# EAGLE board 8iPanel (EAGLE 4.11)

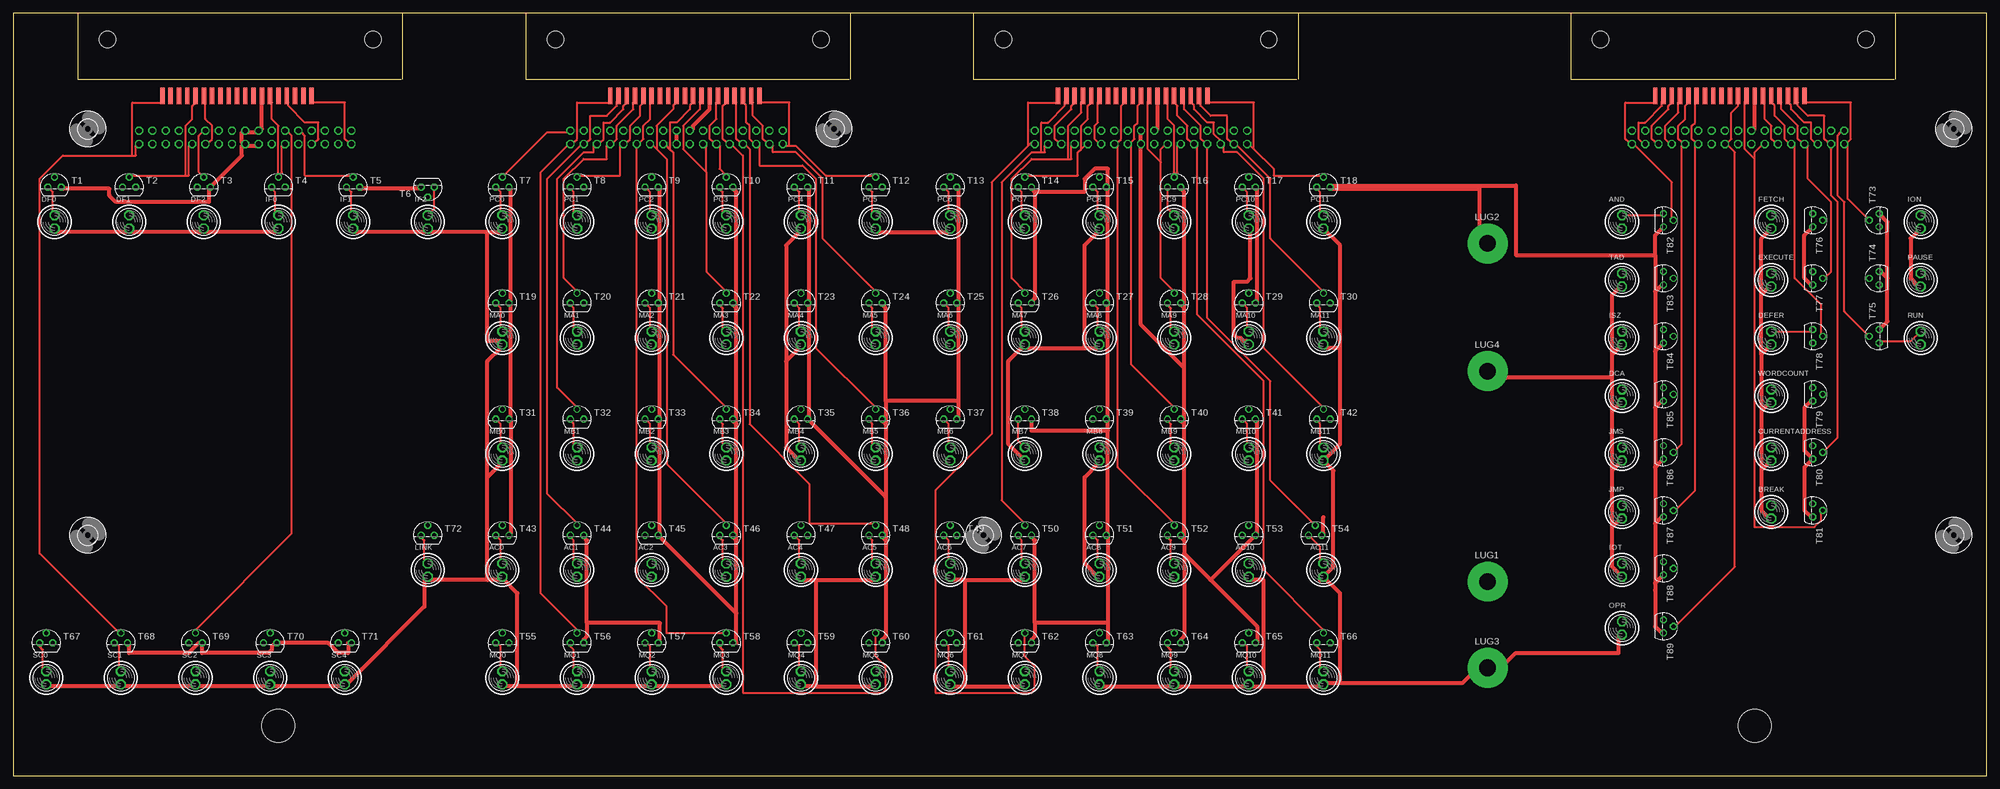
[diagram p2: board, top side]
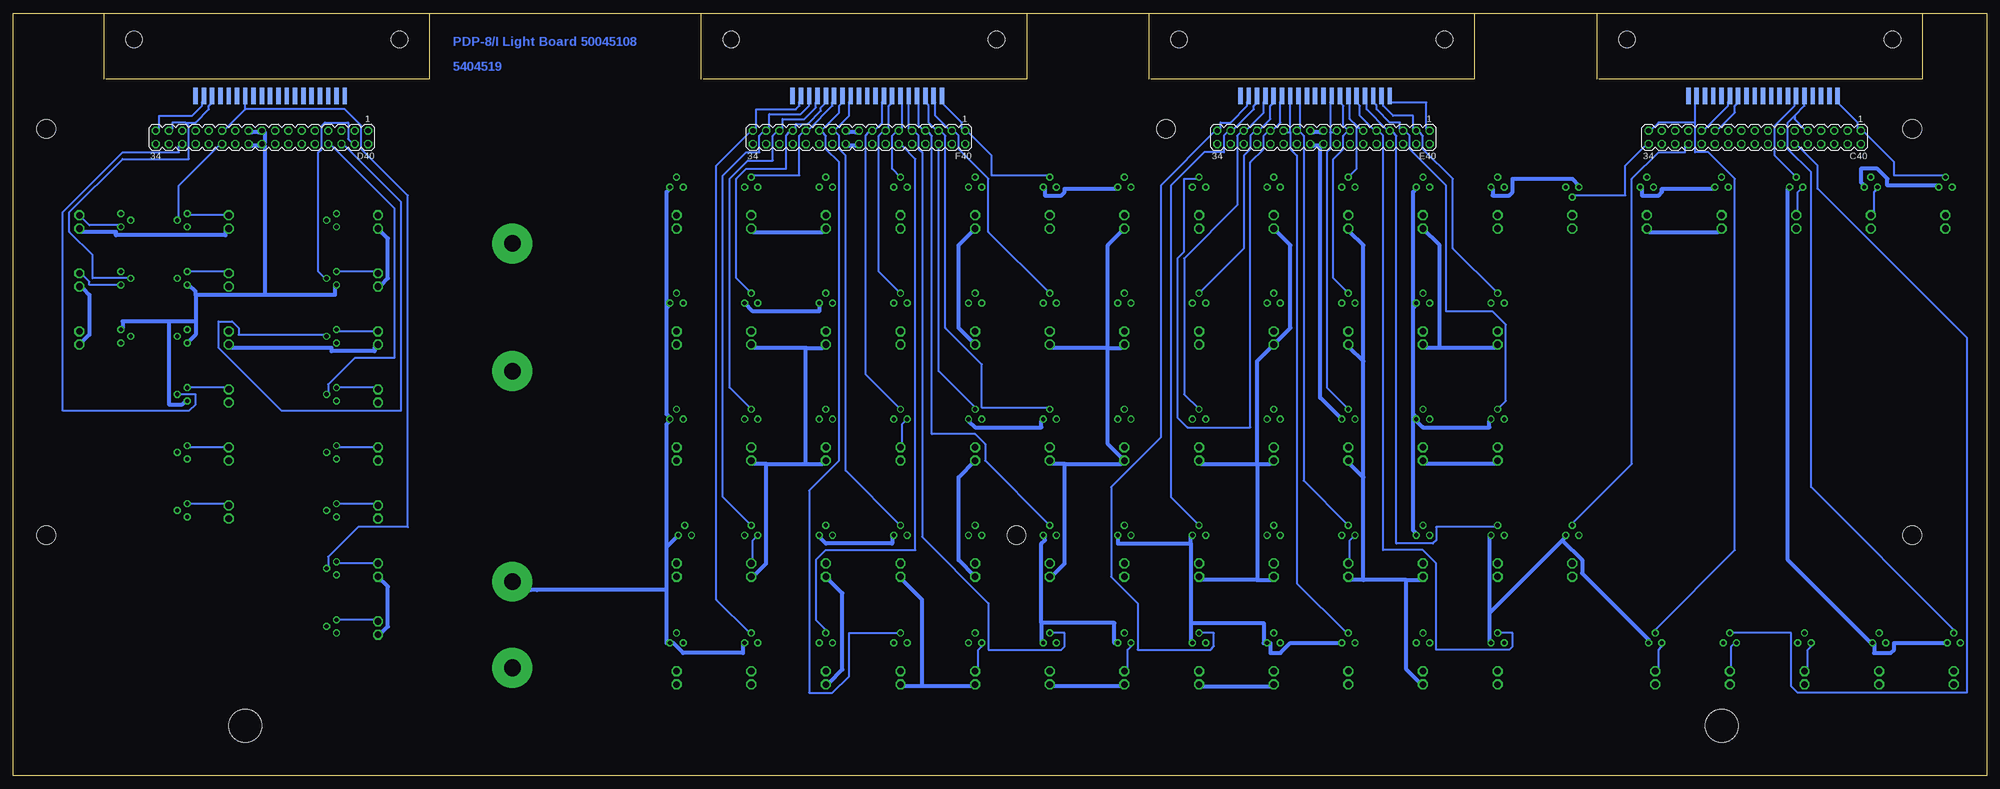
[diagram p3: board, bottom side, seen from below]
Size 377.82 x 146.05 mm. Coordinates in mm from the lower left corner, seen from the top.
Outline: 0,0 377.82,0 377.82,146.05 0,146.05 0,0
Copper layers (1*16): Top 0.035mm / dielectric 1.5mm / Bottom 0.035mm
Design rules "15mils": minimum track width 15mil, minimum drill 24mil, track to track 15mil, track to pad 10mil, pad to pad 10mil, via to via 10mil, smd to smd 10mil, copper to edge 25mil, drill to drill 10mil, minimum pad ring 10mil, minimum via ring 8mil, stop-mask expansion 0mil, vias tented up to drill 0mil, thermal gap 10mil
Net classes: 1 supply: width 0.762 mm
Holes 6.35 mm at 50.8,9.53 333.38,9.53

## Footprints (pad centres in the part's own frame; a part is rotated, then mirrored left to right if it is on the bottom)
BULB = drill 1.27 octagon: A 0,0; B 0,2.54
MA17-2 = drill 1.016 octagon: 1 -20.32,-1.27; 2 -20.32,1.27; 3 -17.78,-1.27; 4 -17.78,1.27; 5 -15.24,-1.27; 6 -15.24,1.27; 7 -12.7,-1.27; 8 -12.7,1.27; 9 -10.16,-1.27; 10 -10.16,1.27; 11 -7.62,-1.27; 12 -7.62,1.27; 13 -5.08,-1.27; 14 -5.08,1.27; 15 -2.54,-1.27; 16 -2.54,1.27; 17 0,-1.27; 18 0,1.27; 19 2.54,-1.27; 20 2.54,1.27; 21 5.08,-1.27; 22 5.08,1.27; 23 7.62,-1.27; 24 7.62,1.27; 25 10.16,-1.27; 26 10.16,1.27; 27 12.7,-1.27; 28 12.7,1.27; 29 15.24,-1.27; 30 15.24,1.27; 31 17.78,-1.27; 32 17.78,1.27; 33 20.32,-1.27; 34 20.32,1.27
FLEX19 = smd 3.175 x 0.838: 1 0,14.287; 2 0,12.7; 3 0,11.113; 4 0,9.525; 5 0,7.938; 6 0,6.35; 7 0,4.763; 8 0,3.175; 9 0,1.587; 10 0,0; 11 0,-1.587; 12 0,-3.175; 13 0,-4.763; 14 0,-6.35; 15 0,-7.938; 16 0,-9.525; 17 0,-11.113; 18 0,-12.7; 19 0,-14.287
SPADELUG = drill 3.175 pad 7.62 round: 1 0,0
TO92 = drill 0.813 octagon: 1 1.27,0; 2 0,1.905; 3 -1.27,0
STRAIN-RELIEF = hole 3.175: 7.62,56.515; 7.62,5.715
3,6 = hole 3.6: 0,0

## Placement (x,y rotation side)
AC0  [BULB]  93.66,38.1 0 top
AC1  [BULB]  107.95,38.1 0 top
AC2  [BULB]  122.24,38.1 0 top
AC3  [BULB]  136.53,38.1 0 top
AC4  [BULB]  150.81,38.1 0 top
AC5  [BULB]  165.1,38.1 0 top
AC6  [BULB]  179.39,38.1 0 top
AC7  [BULB]  193.68,38.1 0 top
AC8  [BULB]  207.96,38.1 0 top
AC9  [BULB]  222.25,38.1 0 top
AC10  [BULB]  236.54,38.1 0 top
AC11  [BULB]  250.82,38.1 0 top
AND  [BULB]  307.98,104.78 0 top
BREAK  [BULB]  336.55,49.21 0 top
C40  [MA17-2]  44.45,122.24 180 bottom
C40BOT  FLEX19  [FLEX19]  42.86,130.18 90 top
C40TOP  FLEX19  [FLEX19]  42.86,130.18 270 bottom
CURRENTADDRESS  [BULB]  336.55,60.33 0 top
D40  [MA17-2]  330.2,122.24 180 bottom
D40BOT  FLEX19  [FLEX19]  128.59,130.18 90 top
D40TOP  FLEX19  [FLEX19]  128.59,130.18 270 bottom
DCA  [BULB]  307.98,71.44 0 top
DEFER  [BULB]  336.55,82.55 0 top
DF0  [BULB]  7.94,104.78 0 top
DF1  [BULB]  22.23,104.78 0 top
DF2  [BULB]  36.51,104.78 0 top
E40  [MA17-2]  127,122.24 180 bottom
E40BOT  FLEX19  [FLEX19]  214.31,130.18 90 top
E40TOP  FLEX19  [FLEX19]  214.31,130.18 270 bottom
EXECUTE  [BULB]  336.55,93.66 0 top
F40  [MA17-2]  215.9,122.24 180 bottom
F40BOT  FLEX19  [FLEX19]  328.61,130.18 90 top
F40TOP  FLEX19  [FLEX19]  328.61,130.18 270 bottom
FETCH  [BULB]  336.55,104.78 0 top
IF0  [BULB]  50.8,104.78 0 top
IF1  [BULB]  65.09,104.78 0 top
IF2  [BULB]  79.38,104.78 0 top
ION  [BULB]  365.12,104.78 0 top
IOT  [BULB]  307.98,38.1 0 top
ISZ  [BULB]  307.98,82.55 0 top
JMP  [BULB]  307.98,49.21 0 top
JMS  [BULB]  307.98,60.33 0 top
LINK  [BULB]  79.38,38.1 0 top
LUG1  LUG  [SPADELUG]  282.26,37.15 0 top
LUG2  LUG  [SPADELUG]  282.26,101.92 0 top
LUG3  LUG  [SPADELUG]  282.26,20.64 0 top
LUG4  LUG  [SPADELUG]  282.26,77.47 0 top
MA0  [BULB]  93.66,82.55 0 top
MA1  [BULB]  107.95,82.55 0 top
MA2  [BULB]  122.24,82.55 0 top
MA3  [BULB]  136.53,82.55 0 top
MA4  [BULB]  150.81,82.55 0 top
MA5  [BULB]  165.1,82.55 0 top
MA6  [BULB]  179.39,82.55 0 top
MA7  [BULB]  193.68,82.55 0 top
MA8  [BULB]  207.96,82.55 0 top
MA9  [BULB]  222.25,82.55 0 top
MA10  [BULB]  236.54,82.55 0 top
MA11  [BULB]  250.82,82.55 0 top
MB0  [BULB]  93.66,60.33 0 top
MB1  [BULB]  107.95,60.33 0 top
MB2  [BULB]  122.24,60.33 0 top
MB3  [BULB]  136.53,60.33 0 top
MB4  [BULB]  150.81,60.33 0 top
MB5  [BULB]  165.1,60.33 0 top
MB6  [BULB]  179.39,60.33 0 top
MB7  [BULB]  193.68,60.33 0 top
MB8  [BULB]  207.96,60.33 0 top
MB9  [BULB]  222.25,60.33 0 top
MB10  [BULB]  236.54,60.33 0 top
MB11  [BULB]  250.82,60.33 0 top
MQ0  [BULB]  93.66,17.46 0 top
MQ1  [BULB]  107.95,17.46 0 top
MQ2  [BULB]  122.24,17.46 0 top
MQ3  [BULB]  136.53,17.46 0 top
MQ4  [BULB]  150.81,17.46 0 top
MQ5  [BULB]  165.1,17.46 0 top
MQ6  [BULB]  179.39,17.46 0 top
MQ7  [BULB]  193.68,17.46 0 top
MQ8  [BULB]  207.96,17.46 0 top
MQ9  [BULB]  222.25,17.46 0 top
MQ10  [BULB]  236.54,17.46 0 top
MQ11  [BULB]  250.82,17.46 0 top
OPR  [BULB]  307.98,26.99 0 top
PAUSE  [BULB]  365.12,93.66 0 top
PC0  [BULB]  93.66,104.78 0 top
PC1  [BULB]  107.95,104.78 0 top
PC2  [BULB]  122.24,104.78 0 top
PC3  [BULB]  136.53,104.78 0 top
PC4  [BULB]  150.81,104.78 0 top
PC5  [BULB]  165.1,104.78 0 top
PC6  [BULB]  179.39,104.78 0 top
PC7  [BULB]  193.68,104.78 0 top
PC8  [BULB]  207.96,104.78 0 top
PC9  [BULB]  222.25,104.78 0 top
PC10  [BULB]  236.54,104.78 0 top
PC11  [BULB]  250.82,104.78 0 top
RUN  [BULB]  365.12,82.55 0 top
SC0  [BULB]  6.35,17.46 0 top
SC1  [BULB]  20.64,17.46 0 top
SC2  [BULB]  34.92,17.46 0 top
SC3  [BULB]  49.21,17.46 0 top
SC4  [BULB]  63.5,17.46 0 top
T1  2N2222  [TO92]  7.94,112.71 0 top
T2  2N2222  [TO92]  22.23,112.71 0 top
T3  2N2222  [TO92]  36.51,112.71 0 top
T4  2N2222  [TO92]  50.8,112.71 0 top
T5  2N2222  [TO92]  65.09,112.71 0 top
T6  2N2222  [TO92]  79.38,112.71 180 top
T7  2N2222  [TO92]  93.66,112.71 0 top
T8  2N2222  [TO92]  107.95,112.71 0 top
T9  2N2222  [TO92]  122.24,112.71 0 top
T10  2N2222  [TO92]  136.53,112.71 0 top
T11  2N2222  [TO92]  150.81,112.71 0 top
T12  2N2222  [TO92]  165.1,112.71 0 top
T13  2N2222  [TO92]  179.39,112.71 0 top
T14  2N2222  [TO92]  193.68,112.71 0 top
T15  2N2222  [TO92]  207.96,112.71 0 top
T16  2N2222  [TO92]  222.25,112.71 0 top
T17  2N2222  [TO92]  236.54,112.71 0 top
T18  2N2222  [TO92]  250.82,112.71 0 top
T19  2N2222  [TO92]  93.66,90.49 0 top
T20  2N2222  [TO92]  107.95,90.49 0 top
T21  2N2222  [TO92]  122.24,90.49 0 top
T22  2N2222  [TO92]  136.53,90.49 0 top
T23  2N2222  [TO92]  150.81,90.49 0 top
T24  2N2222  [TO92]  165.1,90.49 0 top
T25  2N2222  [TO92]  179.39,90.49 0 top
T26  2N2222  [TO92]  193.68,90.49 0 top
T27  2N2222  [TO92]  207.96,90.49 0 top
T28  2N2222  [TO92]  222.25,90.49 0 top
T29  2N2222  [TO92]  236.54,90.49 0 top
T30  2N2222  [TO92]  250.82,90.49 0 top
T31  2N2222  [TO92]  93.66,68.26 0 top
T32  2N2222  [TO92]  107.95,68.26 0 top
T33  2N2222  [TO92]  122.24,68.26 0 top
T34  2N2222  [TO92]  136.53,68.26 0 top
T35  2N2222  [TO92]  150.81,68.26 0 top
T36  2N2222  [TO92]  165.1,68.26 0 top
T37  2N2222  [TO92]  179.39,68.26 0 top
T38  2N2222  [TO92]  193.68,68.26 0 top
T39  2N2222  [TO92]  207.96,68.26 0 top
T40  2N2222  [TO92]  222.25,68.26 0 top
T41  2N2222  [TO92]  236.54,68.26 0 top
T42  2N2222  [TO92]  250.82,68.26 0 top
T43  2N2222  [TO92]  93.66,46.04 0 top
T44  2N2222  [TO92]  107.95,46.04 0 top
T45  2N2222  [TO92]  122.24,46.04 0 top
T46  2N2222  [TO92]  136.53,46.04 0 top
T47  2N2222  [TO92]  150.81,46.04 0 top
T48  2N2222  [TO92]  165.1,46.04 0 top
T49  2N2222  [TO92]  179.39,46.04 0 top
T50  2N2222  [TO92]  193.68,46.04 0 top
T51  2N2222  [TO92]  207.96,46.04 0 top
T52  2N2222  [TO92]  222.25,46.04 0 top
T53  2N2222  [TO92]  236.54,46.04 0 top
T54  2N2222  [TO92]  249.24,46.04 0 top
T55  2N2222  [TO92]  93.66,25.4 0 top
T56  2N2222  [TO92]  107.95,25.4 0 top
T57  2N2222  [TO92]  122.24,25.4 0 top
T58  2N2222  [TO92]  136.53,25.4 0 top
T59  2N2222  [TO92]  150.81,25.4 0 top
T60  2N2222  [TO92]  165.1,25.4 0 top
T61  2N2222  [TO92]  179.39,25.4 0 top
T62  2N2222  [TO92]  193.68,25.4 0 top
T63  2N2222  [TO92]  207.96,25.4 0 top
T64  2N2222  [TO92]  222.25,25.4 0 top
T65  2N2222  [TO92]  236.54,25.4 0 top
T66  2N2222  [TO92]  250.82,25.4 0 top
T67  2N2222  [TO92]  6.35,25.4 0 top
T68  2N2222  [TO92]  20.64,25.4 0 top
T69  2N2222  [TO92]  34.92,25.4 0 top
T70  2N2222  [TO92]  49.21,25.4 0 top
T71  2N2222  [TO92]  63.5,25.4 0 top
T72  2N2222  [TO92]  79.38,46.04 0 top
T73  2N2222  [TO92]  357.19,106.36 90 top
T74  2N2222  [TO92]  357.19,95.25 90 top
T75  2N2222  [TO92]  357.19,84.14 90 top
T76  2N2222  [TO92]  344.49,106.36 270 top
T77  2N2222  [TO92]  344.49,95.25 270 top
T78  2N2222  [TO92]  344.49,84.14 270 top
T79  2N2222  [TO92]  344.49,73.03 270 top
T80  2N2222  [TO92]  344.49,61.91 270 top
T81  2N2222  [TO92]  344.49,50.8 270 top
T82  2N2222  [TO92]  315.91,106.36 270 top
T83  2N2222  [TO92]  315.91,95.25 270 top
T84  2N2222  [TO92]  315.91,84.14 270 top
T85  2N2222  [TO92]  315.91,73.03 270 top
T86  2N2222  [TO92]  315.91,61.91 270 top
T87  2N2222  [TO92]  315.91,50.8 270 top
T88  2N2222  [TO92]  315.91,39.69 270 top
T89  2N2222  [TO92]  315.91,28.57 270 top
TAD  [BULB]  307.98,93.66 0 top
U$1  [STRAIN-RELIEF]  74.61,133.35 90 top
U$2  [STRAIN-RELIEF]  160.34,133.35 90 top
U$3  [STRAIN-RELIEF]  246.06,133.35 90 top
U$4  [STRAIN-RELIEF]  360.36,133.35 90 top
U$5  [3,6]  371.48,123.83 0 top
U$6  [3,6]  371.48,46.04 0 top
U$7  [3,6]  185.74,46.04 0 top
U$8  [3,6]  14.29,46.04 0 top
U$9  [3,6]  14.29,123.83 0 top
U$11  [3,6]  157.16,123.83 0 top
WORDCOUNT  [BULB]  336.55,71.44 0 top

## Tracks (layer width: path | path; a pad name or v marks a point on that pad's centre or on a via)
+15V
  Top 0.762: ION.A 363.22,102.87 363.22,95.25 364.49,93.98 PAUSE.A | 334.64,58.42 334.64,50.8 335.92,49.53 BREAK.A | 334.64,58.42 CURRENTADDRESS.A | 334.64,69.85 335.92,71.12 WORDCOUNT.A | 334.64,69.85 334.64,58.42 | 334.64,80.64 334.64,69.85 | DEFER.A 334.64,80.64 | 334.64,92.08 335.92,93.34 EXECUTE.A | 334.64,80.64 334.64,92.08 | 334.64,92.08 334.64,102.87 FETCH.A | 306.07,47.62 307.34,48.9 JMP.A | 306.07,47.62 306.07,40.01 IOT.A | 306.07,47.62 306.07,58.42 | 306.07,58.42 JMS.A | 306.07,69.85 307.34,71.12 DCA.A | 306.07,58.42 306.07,69.85 | 306.07,69.85 306.07,74.3 306.07,76.2 | 306.07,76.2 306.07,80.64 | 306.07,80.64 ISZ.A | 306.07,80.64 306.07,92.08 307.34,93.34 TAD.A | OPR.A 307.34,26.67 307.34,23.5 287.65,23.5 285.75,21.59 LUG3.1 278.76,19.05 277.5,17.78 254,17.78 | 254,81.92 251.46,81.92 MA11.A | DF0.A 8.26,104.14 21.59,104.14 DF1.A 22.86,104.14 36.2,104.14 DF2.A 36.83,104.14 50.16,104.14 IF0.A | IF1.A 65.41,104.14 78.74,104.14 IF2.A 80.01,104.14 90.81,104.14 | 90.81,104.14 93.34,104.14 PC0.A | 90.81,104.14 90.81,83.19 93.34,83.19 MA0.A 93.34,81.92 90.81,79.38 90.81,57.15 | PC5.A 165.74,104.14 179.07,104.14 PC6.A | 205.1,81.92 207.65,81.92 MA8.A | 205.1,81.92 194.31,81.92 MA7.A 190.5,79.38 190.5,63.5 MB7.A | 205.1,81.92 205.1,101.6 207.65,104.14 PC8.A | 182.25,37.47 193.04,37.47 AC7.A | 182.25,37.47 179.71,37.47 AC6.A | 147.96,79.38 150.5,81.92 MA4.A | 147.96,79.38 147.96,62.87 150.5,60.33 MB4.A | 147.96,79.38 147.96,101.6 150.5,104.14 PC4.A | SC0.A 6.99,17.14 20.32,17.14 SC1.A 20.95,17.14 34.29,17.14 SC2.A 35.56,17.14 48.9,17.14 SC3.A 49.53,17.14 62.87,17.14 SC4.A 64.14,17.78 78.74,32.38 78.74,37.47 LINK.A 80.01,37.47 90.81,37.47
  Top 0.762: AC10.A 236.85,37.47 239.4,37.47 239.4,17.14 | AC11.A 250.19,37.47 | AC11.A 252.73,40.01 252.73,58.42 MB11.A 251.46,60.96 254,63.5 254,81.92 | 153.67,37.47 151.13,37.47 AC4.A | 153.67,37.47 164.47,37.47 AC5.A | 90.81,37.47 93.34,37.47 AC0.A 93.98,37.47 96.52,34.92 96.52,17.14 | 96.52,17.14 107.31,17.14 MQ1.A 108.58,17.14 121.92,17.14 MQ2.A 122.56,17.14 135.89,17.14 MQ3.A | 96.52,17.14 93.98,17.14 MQ0.A | 153.67,17.14 151.13,17.14 MQ4.A | 153.67,17.14 164.47,17.14 MQ5.A | 182.25,17.14 179.71,17.14 MQ6.A | 182.25,17.14 193.04,17.14 MQ7.A | MB8.A 207.65,59.69 205.1,57.15 205.1,40.64 207.65,38.1 AC8.A | MQ8.A 208.28,17.14 221.62,17.14 MQ9.A 222.88,17.14 236.22,17.14 MQ10.A 236.85,17.14 239.4,17.14 | 239.4,17.14 250.19,17.14 MQ11.A 251.46,17.78 254,17.78 | 90.81,57.15 93.34,59.69 MB0.A | 90.81,37.47 90.81,57.15 | 153.67,37.47 153.67,17.14 | 182.25,17.14 182.25,37.47 | 254,81.92 254,101.6 PC11.A | 254,17.78 254,34.92 AC11.A | PC10.A 236.85,104.14 236.85,95.25 236.22,94.61 233.68,94.61 233.68,84.45 234.31,83.82 234.95,83.82 235.59,83.19 236.22,83.19 MA10.A | 306.07,76.2 285.75,76.2 LUG4.1
  Bottom 0.762: RUN.A 363.22,84.45 363.22,92.08 364.49,93.34 PAUSE.A | ION.A 364.49,104.14 358.14,104.14 358.14,103.5 337.19,103.5 337.19,104.14 FETCH.A | 233.68,59.69 226.06,59.69 | 226.06,59.69 222.88,59.69 MB9.A | 233.68,59.69 236.22,59.69 MB10.A | OPR.A 307.34,27.3 306.07,28.57 306.07,36.2 IOT.A | AND.A 306.07,102.87 306.07,95.25 307.34,93.98 TAD.A | DEFER.A 335.92,81.92 316.87,81.92 316.87,81.28 308.61,81.28 308.61,81.92 ISZ.A | 104.78,81.92 107.31,81.92 MA1.A | 104.78,81.92 93.98,81.92 MA0.A | 104.78,81.92 104.78,101.6 PC1.A | IF1.A 64.77,104.14 51.44,104.14 IF0.A | 176.53,59.69 179.07,59.69 MB6.A | 176.53,59.69 165.74,59.69 MB5.A 168.28,63.5 168.28,81.92 | 168.28,81.92 179.07,81.92 MA6.A | 168.28,81.92 165.74,81.92 MA5.A | 168.28,81.92 168.28,101.6 PC5.A | PC7.A 196.85,101.6 196.85,85.72 MA7.A | MB7.A 196.85,57.15 196.85,41.27 AC7.A | 176.53,59.69 176.53,40.64 179.07,38.1 AC6.A | 119.38,37.47 121.92,37.47 AC2.A | 111.12,37.47 119.38,37.47 | 111.12,37.47 108.58,37.47 AC1.A | 119.38,57.15 121.92,59.69 MB2.A | 119.38,37.47 119.38,57.15 | 119.38,79.38 121.92,81.92 MA2.A | 119.38,57.15 119.38,79.38 | 119.38,79.38 119.38,101.6 121.92,104.14 PC2.A | 139.7,59.69 150.5,59.69 MB4.A | 139.7,59.69 137.16,59.69 MB3.A | 139.7,59.69 139.7,79.38 MA3.A 133.35,85.72 133.35,101.6 PC3.A | 139.7,37.47 150.5,37.47 AC4.A | 139.7,37.47 137.16,37.47 AC3.A | MB0.A 93.98,59.69 107.31,59.69 MB1.A | MQ4.A 150.5,17.14 137.16,17.14 MQ3.A | MQ6.A 179.07,17.14 165.74,17.14 MQ5.A | 203.84,17.14 194.31,17.14 MQ7.A | 203.84,17.14 207.65,17.14 MQ8.A | 203.84,17.14 203.84,33.66 207.65,37.47 AC8.A | AC9.A 219.07,34.92 219.07,20.32 221.62,17.78 MQ9.A
  Bottom 0.762: 139.7,59.69 139.7,37.47 | 111.12,37.47 111.12,20.32 108.58,17.78 MQ1.A | 233.68,59.69 233.68,40.64 236.22,38.1 AC10.A | PC9.A 222.88,104.14 236.22,104.14 PC10.A | 226.06,81.92 222.88,81.92 MA9.A | 226.06,59.69 226.06,81.92 | 226.06,81.92 236.22,81.92 MA10.A
AC0
  Bottom 0.381: T43.2 93.98,47.62 105.41,47.62 105.41,45.09 106.05,44.45 113.03,44.45 113.03,122.56 113.67,123.19 E40.7 114.94,123.83 118.75,127.64 118.75,128.91 D40TOP.4
AC1
  Top 0.381: T44.2 107.95,48.26 102.23,53.98 102.23,114.3 108.58,120.65 E40.4 109.86,121.28 110.49,121.92 110.49,126.36 113.67,126.36 115.57,128.27 115.57,128.91 D40BOT.2
AC2
  Bottom 0.381: T45.2 130.81,56.52 130.81,122.56 131.44,123.19 E40.21 131.44,123.83 131.44,128.91 D40TOP.12
AC3
  Top 0.381: 123.19,120.02 122.56,120.65 E40.14 | 123.19,120.02 125.09,118.11 125.09,59.69 136.53,48.26 T46.2 | 123.19,120.02 123.19,124.46 126.36,127.64 126.36,128.27 127,128.91 D40BOT.9
AC4
  Bottom 0.381: T47.2 156.21,53.34 156.21,113.03 149.86,119.38 146.05,119.38 146.05,122.56 145.41,123.19 E40.31 144.15,123.83 140.34,127.64 140.34,128.27 139.7,128.91 D40TOP.17
AC5
  Top 0.381: T48.2 165.1,48.26 152.4,48.26 152.4,55.88 140.97,67.31 140.97,120.02 140.34,120.65 E40.28 139.06,121.28 138.43,121.92 138.43,128.91 D40BOT.16
AC6
  Bottom 0.381: T49.2 191.77,60.33 191.77,63.5 193.68,65.41 201.93,65.41 201.93,122.56 202.56,123.19 F40.7 203.84,123.83 204.47,124.46 204.47,128.91 E40TOP.4
AC7
  Top 0.381: 196.85,119.38 197.49,119.38 197.49,120.65 F40.4 | 196.85,119.38 194.94,119.38 189.23,113.67 189.23,52.7 193.68,48.26 T50.2 | 196.85,119.38 196.85,125.09 198.12,125.09 201.29,128.27 201.29,128.91 E40BOT.2
AC8
  Bottom 0.381: T51.2 218.44,58.42 218.44,118.75 219.71,120.02 219.71,122.56 220.34,123.19 F40.21 220.34,123.83 217.81,126.36 217.81,128.91 E40TOP.12
AC9
  Top 0.381: T52.2 222.25,48.26 211.46,59.05 211.46,120.65 F40.14 211.46,121.28 212.09,121.92 212.09,128.27 212.72,128.91 E40BOT.9
AC10
  Bottom 0.381: T53.2 241.94,53.34 241.94,114.94 237.49,119.38 234.95,119.38 234.95,122.56 234.31,123.19 F40.31 233.04,123.83 233.04,126.68 227.01,126.68 225.43,128.27 E40TOP.17
AC11
  Top 0.381: T54.2 240.66,56.52 240.66,75.56 228.6,87.63 F40.28 227.97,121.28 227.33,121.92 227.33,124.46 224.16,127.64 224.16,128.91 E40BOT.16
AND
  Top 0.381: T82.2 317.5,106.68 317.5,113.67 310.51,120.65 D40.2 309.25,121.28 308.61,121.92 308.61,128.91 314.32,128.91 F40BOT.1
BREAK
  Top 0.381: 333.38,118.11 333.38,119.38 334.64,120.65 D40.22 | 333.38,118.11 333.38,47.62 344.81,47.62 346.07,48.9 346.07,50.8 T81.2 | 333.38,118.11 331.47,120.02 331.47,128.91 F40BOT.12
CA
  Top 0.381: T80.2 349.25,64.77 349.25,109.86 347.98,111.12 D40.32 347.35,121.28 346.71,121.92 346.71,126.36 343.54,126.36 341.63,128.27 341.63,128.91 F40BOT.18
DCA
  Top 0.381: F40BOT.4 318.77,128.91 318.77,127 316.23,124.46 316.23,121.92 316.87,121.28 D40.8
  Bottom 0.381: T85.2 317.5,73.03 317.5,74.93 312.42,80.01 304.8,80.01 304.8,108.58 316.87,120.65 D40.8
DEFER
  Top 0.381: T78.2 346.07,84.45 346.07,90.17 341,95.25 341,120.65 D40.26 339.73,121.28 339.09,121.92 339.09,124.46 337.19,126.36 337.19,128.27 336.55,128.91 F40BOT.15
DF0
  Bottom 0.381: T1.2 8.26,114.94 17.78,114.94 17.78,117.47 23.5,123.19 C40.1 24.77,123.83 24.77,125.09 28.57,128.91 C40TOP.1
DF1
  Top 0.381: 33.02,114.94 33.66,114.94 33.66,120.65 C40.10 | 33.02,114.94 22.23,114.94 T2.2 | 33.02,114.94 33.02,124.46 34.29,125.73 34.29,128.27 34.92,128.91 C40BOT.5
DF2
  Top 0.381: T3.2 35.56,115.57 35.56,122.56 36.2,123.19 C40.11
  Bottom 0.381: C40TOP.6 36.83,128.91 36.83,128.27 40.64,124.46 40.64,118.75 T3.2
EXECUTE
  Top 0.381: T77.2 346.71,95.25 347.98,96.52 347.98,109.86 343.54,114.3 343.54,120.65 D40.28 342.26,121.28 341.63,121.92 341.63,124.46 338.45,127.64 338.45,128.91 F40BOT.16
FETCH
  Top 0.381: F40BOT.14 335.28,128.91 335.28,125.73 336.55,124.46 336.55,121.92 337.19,121.28 D40.24
  Bottom 0.381: T76.2 346.07,106.68 346.07,113.03 338.45,120.65 D40.24
GND
  Top 0.762: T76.1 342.9,103.5 342.9,95.25 344.17,93.98 T77.1 | 358.77,95.25 358.77,87 T75.1 | 358.77,95.25 357.5,96.52 T74.1 | 358.77,95.25 358.77,106.05 T73.1 | 314.32,36.83 314.32,35.56 314.32,28.57 315.6,27.3 T89.1 | 314.32,36.83 T88.1 | 314.32,48.26 315.6,49.53 T87.1 | 314.32,48.26 314.32,36.83 | 314.32,59.05 314.32,48.26 | 314.32,59.05 T86.1 | 314.32,70.48 315.6,71.75 T85.1 | 314.32,70.48 314.32,59.05 | 314.32,81.28 314.32,70.48 | 314.32,81.28 T84.1 | 314.32,92.71 315.6,93.98 T83.1 | 314.32,92.71 314.32,81.28 | 314.32,99.69 314.32,92.71 | 314.32,99.69 314.32,103.5 T82.1 | T41.1 238.12,67.94 238.12,46.35 T53.1 229.24,37.47 | 224.16,45.09 224.16,42.55 | 224.16,42.55 224.16,26.67 223.52,26.04 T64.1 | 224.16,45.09 223.52,45.72 T52.1 | 224.16,67.31 223.52,67.94 T40.1 | 224.16,45.09 224.16,67.31 | 224.16,89.53 223.52,90.17 T28.1 | 224.16,67.31 224.16,78.11 | 224.16,78.11 224.16,89.53 | 224.16,42.55 229.24,37.47 | 229.24,37.47 238.12,28.57 238.12,25.4 T65.1 | 250.82,49.53 250.82,46.35 T54.1 | 314.32,99.69 287.65,99.69 287.65,113.03 252.09,113.03 T18.1 252.09,112.39 280.67,112.39 280.67,105.41 LUG2.1 | 195.58,111.76 195.58,91.44 194.94,90.81 T26.1 | 195.58,111.76 194.94,112.39 T14.1 | 195.58,29.21 195.58,45.09 194.94,45.72 T50.1 | 195.58,29.21 195.58,26.67 194.94,26.04 T62.1 | 209.55,29.21 209.55,45.72 T51.1 209.55,46.35 209.55,66.04 | 209.55,29.21 209.55,25.4 T63.1 | 209.55,66.04 209.55,67.94 T39.1 209.55,68.58 209.55,90.17 T27.1 209.55,90.81 209.55,112.39 T15.1 209.55,113.03 209.55,116.2 207.01,116.2 205.1,114.3 205.1,111.76 195.58,111.76 | 209.55,29.21 195.58,29.21 | 180.97,71.75 180.97,90.17 T25.1 180.97,90.81 180.97,112.39 T13.1
  Top 0.762: 180.97,71.75 180.97,68.58 T37.1 | T11.1 152.4,112.39 152.4,90.81 T23.1 152.4,90.17 152.4,68.58 T35.1 167,53.34 | 167,45.09 167,26.67 166.37,26.04 T60.1 | 167,45.09 166.37,45.72 T48.1 | 167,67.31 166.37,67.94 T36.1 | 167,53.34 167,45.09 | 167,67.31 167,53.34 | 167,71.75 167,67.31 | 167,71.75 167,89.53 166.37,90.17 T24.1 | 180.97,71.75 167,71.75 | 209.55,66.04 194.94,66.04 T38.1 | 109.86,29.21 109.86,45.09 109.22,45.72 T44.1 | 109.86,29.21 109.86,26.67 109.22,26.04 T56.1 | 109.86,29.21 123.83,29.21 123.83,25.4 T57.1 | T9.1 123.83,112.39 123.83,90.81 T21.1 123.83,90.17 123.83,68.58 T33.1 123.83,67.94 123.83,46.35 T45.1 138.43,31.11 | T1.1 9.53,112.39 18.41,112.39 18.41,111.12 19.68,109.86 37.47,109.86 37.47,112.39 T3.1 43.81,118.75 43.81,120.65 C40.18 | T71.1 64.14,25.4 64.14,23.5 62.23,23.5 60.33,25.4 T70.1 50.16,25.4 49.53,24.77 49.53,24.13 48.9,23.5 36.2,23.5 T69.1 35.56,25.4 33.66,23.5 22.23,23.5 22.23,25.4 T68.1 | T6.1 78.11,112.39 66.67,112.39 T5.1 | T43.1 95.25,46.35 95.25,67.94 T31.1 95.25,68.58 95.25,90.17 T19.1 95.25,90.81 95.25,112.39 T7.1 | T29.1 238.12,90.81 238.12,112.39 T17.1 | C40.18 45.09,120.65 46.35,120.65 C40.20 | C40BOT.13 47.62,123.83 C40.19 46.35,123.19 45.09,123.19 C40.17 43.81,123.19 43.81,121.28 C40.18 | F40BOT.13 333.38,123.83 D40.19 | T81.1 344.17,49.53 342.9,50.8 342.9,59.05 T80.1 342.9,62.23 342.9,70.48 344.17,71.75 T79.1 | D40BOT.13 133.35,127.64 130.18,124.46 130.18,123.83 E40.19 | E40.18 E40.17 | 138.43,45.09 137.79,45.72 T46.1 | 138.43,31.11 138.43,25.4 T58.1 | 138.43,31.11 138.43,45.09 | 138.43,67.31 137.79,67.94 T34.1 | 138.43,45.09 138.43,67.31
  Top 0.762: 138.43,89.53 137.79,90.17 T22.1 | 138.43,67.31 138.43,89.53 | 138.43,89.53 138.43,111.76 137.79,112.39 T10.1 | E40BOT.13 219.07,123.83 F40.19 | F40.17 F40.18 215.9,86.36 224.16,78.11 | 224.16,89.53 224.16,111.76 223.52,112.39 T16.1
  Bottom 0.762: 342.9,92.08 342.9,92.71 344.17,93.98 T77.1 | 342.9,92.08 342.9,87 | 342.9,87 342.9,84.45 T78.1 | 347.98,87 356.87,87 356.87,85.72 T75.1 | 342.9,87 347.98,87 | 329.56,92.08 316.23,92.08 316.23,93.98 T83.1 | 329.56,92.08 342.9,92.08 | 347.98,87 347.98,71.12 345.44,71.12 344.81,71.75 T79.1 | T65.1 238.12,25.4 238.12,23.5 249.56,23.5 251.46,25.4 T66.1 252.73,25.4 252.73,35.56 | T12.1 166.37,112.39 176.53,112.39 176.53,111.76 177.16,111.12 180.34,111.12 180.34,112.39 T13.1 | T38.1 194.94,67.94 193.68,66.67 180.97,66.67 180.97,67.94 T37.1 | 180.97,29.21 180.97,44.45 180.34,45.09 180.34,45.72 T49.1 | 180.97,29.21 180.97,25.4 T61.1 | 152.4,44.45 152.4,45.72 T47.1 | 152.4,44.45 152.4,29.21 | 152.4,29.21 152.4,25.4 T59.1 | 152.4,44.45 166.37,44.45 T48.1 | 180.97,29.21 167,29.21 167,25.4 T60.1 | T57.1 133.35,25.4 135.25,23.5 137.16,23.5 137.16,25.4 T58.1 138.43,25.4 138.43,29.21 152.4,29.21 | T1.1 9.53,113.03 19.05,113.03 19.05,114.3 20.95,116.2 24.13,116.2 24.13,113.67 23.5,113.03 T2.1 | T67.1 17.78,25.4 17.78,24.13 18.41,23.5 21.59,23.5 21.59,25.4 T68.1 22.23,25.4 38.1,41.27 38.1,112.39 T3.1 | T4.1 52.07,112.39 62.23,112.39 62.23,111.76 62.87,111.12 66.04,111.12 66.04,112.39 T5.1 | 95.25,31.11 95.25,45.72 T43.1 | 95.25,31.11 95.25,25.4 T55.1 | 95.25,31.11 81.28,45.09 | 81.28,45.09 80.64,45.72 T72.1 | T31.1 95.25,67.94 95.25,66.67 107.95,66.67 109.22,67.94 T32.1 109.22,68.58 109.86,69.22 | 109.86,89.53 109.22,90.17 T20.1 | 109.86,69.22 109.86,89.53 | 109.86,89.53 109.86,111.76 109.22,112.39 T8.1 | T6.1 78.11,113.03 79.38,114.3 90.81,114.3 90.81,111.76 91.44,111.12 94.61,111.12 94.61,112.39 T7.1
  Bottom 0.762: 81.28,45.09 77.47,41.27 77.47,38.73 64.77,26.04 T71.1 | 109.86,69.22 109.86,46.99 109.22,46.35 T44.1 | T52.1 223.52,45.72 222.25,44.45 209.55,44.45 209.55,45.72 T51.1 | 252.73,89.53 252.73,69.22 252.09,68.58 T42.1 252.09,67.94 252.73,67.31 252.73,43.81 | 252.73,89.53 252.09,90.17 T30.1 | 252.73,89.53 252.73,111.76 252.09,112.39 T18.1 | 252.73,35.56 252.73,43.81 | 252.73,43.81 T54.1 | 252.73,35.56 277.5,35.56 278.76,35.56 LUG1.1 | D40.18 330.83,120.65 332.11,120.65 D40.20 | D40.19 332.11,123.19 330.83,123.19 D40.17 329.56,123.19 329.56,121.28 D40.18 | 329.56,92.08 329.56,120.65 D40.18 | 127.64,120.65 128.91,120.65 E40.20 | E40.17 127.64,123.19 128.91,123.19 E40.19 | 127.64,120.65 127.64,72.39 T33.1 | 127.64,120.65 E40.18 | F40.18 216.53,120.65 217.81,120.65 F40.20 | F40.17 216.53,123.19 217.81,123.19 F40.19 | T29.1 236.22,88.9 223.52,88.9 T28.1
IF0
  Top 0.381: 50.8,114.94 51.44,115.57 51.44,120.65 C40.24 | 50.8,114.94 50.8,124.46 49.53,125.73 49.53,128.91 C40BOT.14 | T4.2 50.8,114.94
IF1
  Top 0.381: T5.2 64.77,114.94 55.88,114.94 55.88,122.56 55.24,123.19 C40.25
  Bottom 0.381: C40TOP.14 49.53,128.91 49.53,128.27 53.98,123.83 C40.25
IF2
  Top 0.381: C40BOT.19 57.15,128.91 63.5,128.91 63.5,121.92 64.14,121.28 C40.34
  Bottom 0.381: T6.2 79.38,111.12 69.22,111.12 69.22,116.84 65.41,120.65 C40.34
ION
  Top 0.381: T73.2 351.15,110.49 351.15,120.65 D40.34 351.15,121.28 351.79,121.92 351.79,128.91 342.9,128.91 F40BOT.19
IOT
  Bottom 0.381: 333.38,127.64 314.32,127.64 311.15,124.46 311.15,120.02 302.26,111.12 302.26,47.62 311.79,47.62 317.5,41.91 317.5,40.01 T88.2 | 333.38,127.64 F40TOP.13 | 333.38,127.64 337.19,123.83 D40.23
ISZ
  Top 0.381: F40BOT.3 317.5,128.91 316.87,128.27 316.87,127.64 313.69,124.46 313.69,121.92 314.32,121.28 D40.6
  Bottom 0.381: T84.2 318.13,84.45 334.64,84.45 334.64,85.72 335.92,87 338.45,87 338.45,81.92 326.39,69.85 303.53,69.85 303.53,109.86 314.32,120.65 D40.6
JMP
  Top 0.381: T87.2 318.13,50.8 321.94,54.61 321.94,120.65 D40.12 321.94,121.28 321.31,121.92 321.31,124.46 321.94,125.09 321.94,128.91 F40BOT.6
JMS
  Top 0.381: T86.2 319.4,63.5 319.4,120.65 D40.10 319.4,121.28 318.77,121.92 318.77,124.46 320.04,125.73 320.04,128.27 320.68,128.91 F40BOT.5
LINK
  Top 0.381: C40BOT.16 52.7,128.91 52.7,128.27 55.88,125.09 58.42,125.09 58.42,121.92 57.78,121.28 C40.28
  Bottom 0.381: T72.2 79.38,48.26 67.94,59.69 67.94,114.3 62.87,119.38 57.78,119.38 57.78,120.65 C40.28
MA0
  Bottom 0.381: T19.2 102.23,100.97 102.23,114.3 107.95,120.02 107.95,122.56 108.58,123.19 E40.3 109.86,123.83 109.86,126.36 113.67,126.36 115.57,128.27 115.57,128.91 D40TOP.2
MA1
  Top 0.381: T20.2 107.95,92.71 105.41,95.25 105.41,114.3 109.22,118.11 113.67,118.11 113.67,120.65 E40.8 114.94,121.28 115.57,121.92 115.57,124.46 118.75,127.64 118.75,128.91 D40BOT.4
MA2
  Bottom 0.381: D40TOP.7 123.83,128.91 123.19,128.27 123.19,124.46 122.56,123.83 E40.13 | 125.09,118.11 125.09,95.25 T21.2
  Bottom 0.406: E40.13 122.24,123.51 123.19,122.56 123.19,120.02 125.09,118.11
MA3
  Top 0.381: 132.72,115.57 132.72,120.65 E40.22 | 132.72,115.57 132.72,96.52 136.53,92.71 T22.2 | 132.72,115.57 128.27,120.02 128.27,124.46 131.44,127.64 131.44,128.91 D40BOT.12
MA4
  Bottom 0.381: T23.2 142.24,100.97 142.24,118.75 140.97,120.02 140.97,122.56 140.34,123.19 E40.27 139.06,123.83 137.16,125.73 137.16,128.27 136.53,128.91 D40TOP.15
MA5
  Top 0.381: T24.2 165.1,92.71 154.94,102.87 154.94,114.3 149.86,119.38 145.41,119.38 145.41,120.65 E40.32 144.15,121.28 143.51,121.92 143.51,124.46 141.6,126.36 141.6,128.91 D40BOT.18
MA6
  Bottom 0.381: T25.2 191.13,104.14 191.13,114.3 196.85,120.02 196.85,122.56 197.49,123.19 F40.3 198.75,123.83 201.29,126.36 201.29,128.91 E40TOP.2
MA7
  Top 0.381: 201.93,118.11 202.56,118.11 202.56,120.65 F40.8 | 201.93,118.11 194.94,118.11 191.13,114.3 191.13,95.25 193.68,92.71 T26.2 | 201.93,118.11 201.93,124.46 204.47,127 204.47,128.91 E40BOT.4
MA8
  Bottom 0.381: T27.2 212.09,96.52 212.09,122.56 211.46,123.19 F40.13 210.19,123.83 210.19,128.27 209.55,128.91 E40TOP.7
MA9
  Top 0.381: 219.71,117.47 219.71,120.02 220.34,120.65 F40.22 | 219.71,117.47 219.71,95.25 222.25,92.71 T28.2 | 219.71,117.47 217.17,120.02 217.17,128.91 E40BOT.12
MA10
  Bottom 0.381: E40TOP.15 222.25,128.91 223.2,127.95 223.2,127.32 225.74,124.78 227.97,124.78 227.97,123.83 F40.27 229.24,123.19 229.87,122.56 229.87,116.2 237.49,116.2 239.4,114.3 239.4,95.25 T29.2
MA11
  Top 0.381: E40BOT.18 227.33,128.91 227.33,128.27 229.24,126.36 232.41,126.36 232.41,121.92 233.04,121.28 F40.32 234.31,120.65 240.66,114.3 240.66,102.87 250.82,92.71 T30.2
MB0
  Bottom 0.381: T31.2 92.08,71.75 92.08,86.36 94.61,88.9 103.5,88.9 103.5,113.03 110.49,120.02 110.49,122.56 111.12,123.19 E40.5 112.39,123.83 112.39,125.09 114.3,125.09 116.84,127.64 116.84,128.27 117.47,128.91 D40TOP.3
MB1
  Top 0.381: T32.2 107.95,70.48 104.14,74.3 104.14,114.3 109.22,119.38 111.12,119.38 111.12,120.65 E40.6 112.39,121.28 113.03,121.92 113.03,125.09 114.3,125.09 116.84,127.64 116.84,128.27 117.47,128.91 D40BOT.3
MB2
  Bottom 0.381: 125.73,123.19 125.73,128.91 D40TOP.8 | 125.73,123.19 125.09,123.19 E40.15 | T33.2 126.36,74.3 126.36,119.38 125.73,120.02 125.73,123.19
MB3
  Top 0.381: 125.73,120.02 125.09,120.65 E40.16 | 125.73,120.02 126.36,119.38 126.36,80.64 136.53,70.48 T34.2 | 125.73,120.02 125.73,125.09 127,125.09 129.54,127.64 129.54,128.27 130.18,128.91 D40BOT.11
MB4
  Bottom 0.381: T35.2 153.67,73.03 153.67,99.06 143.51,109.22 143.51,122.56 142.88,123.19 E40.29 141.6,123.83 138.43,127 138.43,128.91 D40TOP.16
MB5
  Top 0.381: T36.2 165.1,70.48 153.67,81.92 153.67,114.3 151.13,116.84 142.88,116.84 142.88,120.65 E40.30 141.6,121.28 140.97,121.92 140.97,124.46 140.34,125.09 140.34,128.27 139.7,128.91 D40BOT.17
MB6
  Bottom 0.381: T37.2 179.71,70.48 192.41,70.48 192.41,78.74 199.39,85.72 199.39,122.56 200.03,123.19 F40.5 201.29,123.83 202.56,125.09 202.56,128.27 203.2,128.91 E40TOP.3
MB7
  Top 0.381: E40BOT.3 203.2,128.91 202.56,128.27 202.56,127.64 199.39,124.46 199.39,121.92 200.03,121.28 F40.6
  Bottom 0.381: T38.2 193.68,70.48 200.66,77.47 F40.6
MB8
  Bottom 0.381: T39.2 214.63,76.83 214.63,122.56 214,123.19 F40.15 212.72,123.83 211.46,125.09 211.46,128.91 E40TOP.8
MB9
  Top 0.381: T40.2 222.25,70.48 214,78.74 214,120.65 F40.16 214,121.28 214.63,121.92 214.63,124.46 215.26,125.09 215.26,128.27 215.9,128.91 E40BOT.11
MB10
  Bottom 0.381: E40TOP.16 224.16,128.91 224.16,127.95 226.38,125.73 230.5,125.73 230.5,123.83 F40.29 231.78,123.19 232.41,122.56 232.41,117.79 237.17,117.79 240.66,114.3 240.66,74.3 T41.2
MB11
  Top 0.381: E40BOT.17 225.43,128.91 226.06,128.27 226.06,127.64 228.6,125.09 229.87,125.09 229.87,122.87 231.14,121.6 F40.30 231.78,120.65 231.78,119.38 234.31,119.38 239.4,114.3 239.4,81.92 250.82,70.48 T42.2
MQ0
  Bottom 0.381: T55.2 90.81,27.3 90.81,24.77 91.44,24.13 105.41,24.13 105.41,40.64 107.95,43.18 115.57,43.18 115.57,122.56 116.2,123.19 E40.9 117.47,123.83 120.02,126.36 120.02,128.27 120.65,128.91 D40TOP.5
MQ1
  Top 0.381: T56.2 107.95,27.94 100.97,34.92 100.97,115.57 106.05,120.65 E40.2 107.31,121.28 107.95,121.92 107.95,128.91 114.3,128.91 D40BOT.1
MQ2
  Bottom 0.381: 133.35,123.19 133.35,120.02 132.08,118.75 132.08,36.83 122.56,27.3 T57.2 | 133.35,123.19 D40TOP.13 | 133.35,123.19 133.99,123.19 E40.23
MQ3
  Top 0.381: T58.2 125.09,27.3 125.09,32.38 119.38,38.1 E40.12 120.02,121.28 120.65,121.92 120.65,124.46 121.92,125.73 121.92,128.91 D40BOT.6
MQ4
  Bottom 0.381: T59.2 147.96,27.3 147.96,24.77 148.59,24.13 162.56,24.13 162.56,33.02 167.64,38.1 167.64,55.24 158.12,64.77 158.12,113.03 147.96,123.19 E40.33 146.69,123.83 146.69,125.09 144.78,125.09 141.6,128.27 141.6,128.91 D40TOP.18
MQ5
  Top 0.381: T60.2 165.1,22.86 167,20.95 167,16.51 166.37,15.88 139.7,15.88 139.7,118.75 137.79,120.65 E40.26 136.53,121.28 135.89,121.92 135.89,128.27 136.53,128.91 D40BOT.15
MQ6
  Bottom 0.381: T61.2 176.53,27.3 176.53,24.77 177.16,24.13 191.13,24.13 191.13,33.02 203.84,45.72 203.84,119.38 204.47,120.02 204.47,122.56 205.1,123.19 F40.9 206.38,123.83 E40TOP.5
MQ7
  Top 0.381: 194.31,120.65 194.94,121.28 F40.2 | 194.31,120.65 187.32,113.67 187.32,65.41 176.53,54.61 176.53,15.88 194.94,15.88 195.58,16.51 195.58,20.95 193.68,22.86 T62.2 | 194.31,120.65 194.31,128.91 200.03,128.91 E40BOT.1
MQ8
  Bottom 0.381: T63.2 217.81,27.3 217.81,19.05 220.98,15.88 225.43,15.88 225.43,54.61 219.71,60.33 219.71,117.47 222.25,120.02 222.25,122.56 222.88,123.19 F40.23 222.88,123.83 219.71,127 219.71,128.27 219.07,128.91 E40TOP.13
MQ9
  Top 0.381: E40BOT.6 207.65,128.91 207.65,125.09 207.01,124.46 207.01,121.92 207.65,121.28 F40.12
  Bottom 0.381: T64.2 222.25,27.94 224.16,29.84 224.16,41.27 222.25,43.18 205.1,43.18 205.1,118.11 207.65,120.65 F40.12
MQ10
  Bottom 0.381: T65.2 236.85,27.3 243.21,33.66 243.21,116.84 236.85,123.19 F40.33 235.59,123.83 235.59,127.64 227.97,127.64 227.33,128.27 227.33,128.91 E40TOP.18
MQ11
  Top 0.381: T66.2 250.82,27.94 239.4,39.37 239.4,75.56 226.69,88.27 226.69,120.65 F40.26 225.43,121.28 224.79,121.92 224.79,124.46 222.88,126.36 222.88,128.27 222.25,128.91 E40BOT.15
N$1
  Top 0.381: T1.3 7.62,111.76 7.62,107.95 DF0.B
N$2
  Bottom 0.381: T2.3 20.95,112.39 21.59,111.76 21.59,107.95 DF1.B
N$3
  Bottom 0.381: T3.3 36.2,111.76 36.2,107.95 DF2.B
N$4
  Top 0.381: T4.3 49.53,112.39 50.16,111.76 50.16,107.95 IF0.B
N$5
  Top 0.381: T5.3 64.77,111.76 64.77,107.95 IF1.B
N$6
  Top 0.381: T6.3 80.64,108.58 IF2.B
N$7
  Top 0.381: T7.3 93.34,111.76 93.34,107.95 PC0.B
N$8
  Top 0.381: T8.3 106.68,112.39 107.31,111.76 107.31,107.95 PC1.B
N$9
  Top 0.381: T9.3 121.92,111.76 121.92,107.95 PC2.B
N$10
  Top 0.381: T10.3 135.25,112.39 135.89,111.76 135.89,107.95 PC3.B
N$11
  Top 0.381: T11.3 150.5,111.76 150.5,107.95 PC4.B
N$12
  Top 0.381: T12.3 163.83,112.39 164.47,111.76 164.47,107.95 PC5.B
N$13
  Top 0.381: T13.3 179.07,111.76 179.07,107.95 PC6.B
N$14
  Top 0.381: T14.3 192.41,112.39 193.04,111.76 193.04,107.95 PC7.B
N$15
  Top 0.381: T15.3 207.65,111.76 207.65,107.95 PC8.B
N$16
  Top 0.381: T16.3 220.98,108.58 PC9.B
N$17
  Top 0.381: T17.3 236.22,111.76 236.22,107.95 PC10.B
N$18
  Top 0.381: T18.3 249.56,112.39 250.19,111.76 250.19,107.95 PC11.B
N$19
  Top 0.381: T19.3 93.34,89.53 93.34,85.72 MA0.B
N$20
  Top 0.381: T20.3 106.68,90.17 107.31,89.53 107.31,85.72 MA1.B
N$21
  Top 0.381: T21.3 121.92,89.53 121.92,85.72 MA2.B
N$22
  Top 0.381: T22.3 135.25,90.17 135.89,89.53 135.89,85.72 MA3.B
N$23
  Top 0.381: T23.3 150.5,89.53 150.5,85.72 MA4.B
N$24
  Top 0.381: T24.3 163.83,90.17 164.47,89.53 164.47,85.72 MA5.B
N$25
  Top 0.381: T25.3 179.07,89.53 179.07,85.72 MA6.B
N$26
  Top 0.381: T26.3 192.41,90.17 193.04,89.53 193.04,85.72 MA7.B
N$27
  Top 0.381: T27.3 207.65,89.53 207.65,85.72 MA8.B
N$28
  Top 0.381: T28.3 220.98,90.17 221.62,89.53 221.62,85.72 MA9.B
N$29
  Top 0.381: T29.3 236.22,89.53 236.22,85.72 MA10.B
N$30
  Top 0.381: T30.3 249.56,90.17 250.19,89.53 250.19,85.72 MA11.B
N$31
  Top 0.381: T31.3 93.34,67.31 93.34,63.5 MB0.B
N$32
  Top 0.381: T32.3 106.68,67.94 107.31,67.31 107.31,63.5 MB1.B
N$33
  Top 0.381: T33.3 121.92,67.31 121.92,63.5 MB2.B
N$34
  Top 0.381: T34.3 135.25,67.94 135.89,67.31 135.89,63.5 MB3.B
N$35
  Top 0.381: T35.3 150.5,67.31 150.5,63.5 MB4.B
N$36
  Top 0.381: T36.3 163.83,67.94 164.47,67.31 164.47,63.5 MB5.B
N$37
  Top 0.381: T37.3 179.07,67.31 179.07,63.5 MB6.B
N$38
  Top 0.381: T38.3 192.41,64.14 MB7.B
N$39
  Bottom 0.381: T39.3 207.65,67.31 207.65,63.5 MB8.B
N$40
  Top 0.381: T40.3 220.98,67.94 221.62,67.31 221.62,63.5 MB9.B
N$41
  Top 0.381: T41.3 236.22,67.31 236.22,63.5 MB10.B
N$42
  Top 0.381: T42.3 249.56,67.94 250.19,67.31 250.19,63.5 MB11.B
N$43
  Top 0.381: T43.3 93.34,45.09 93.34,41.27 AC0.B
N$44
  Top 0.381: T44.3 106.68,45.72 107.31,45.09 107.31,41.27 AC1.B
N$45
  Bottom 0.381: T45.3 121.92,45.09 121.92,41.27 AC2.B
N$46
  Top 0.381: T46.3 135.25,45.72 135.89,45.09 135.89,41.27 AC3.B
N$47
  Top 0.381: T47.3 150.5,45.09 150.5,41.27 AC4.B
N$48
  Top 0.381: T48.3 163.83,45.72 164.47,45.09 164.47,41.27 AC5.B
N$49
  Top 0.381: T49.3 179.07,45.09 179.07,41.27 AC6.B
N$50
  Top 0.381: T50.3 192.41,45.72 193.04,45.09 193.04,41.27 AC7.B
N$51
  Top 0.381: T51.3 207.65,45.09 207.65,41.27 AC8.B
N$52
  Top 0.381: T52.3 220.98,45.72 221.62,45.09 221.62,41.27 AC9.B
N$53
  Bottom 0.381: T53.3 236.22,45.09 236.22,41.27 AC10.B
N$54
  Top 0.381: T54.3 250.19,43.81 250.19,41.27 AC11.B
N$55
  Top 0.381: T55.3 92.71,25.4 93.34,24.77 93.34,20.32 MQ0.B
N$56
  Top 0.381: T56.3 106.68,24.77 107.31,24.13 107.31,20.32 MQ1.B
N$57
  Top 0.381: T57.3 121.28,25.4 121.92,24.77 121.92,20.32 MQ2.B
N$58
  Top 0.381: T58.3 135.25,24.77 135.89,24.13 135.89,20.32 MQ3.B
N$59
  Top 0.381: T59.3 149.86,25.4 150.5,24.77 150.5,20.32 MQ4.B
N$60
  Bottom 0.381: T60.3 163.83,24.77 164.47,24.13 164.47,20.32 MQ5.B
N$61
  Top 0.381: T61.3 178.44,25.4 179.07,24.77 179.07,20.32 MQ6.B
N$62
  Bottom 0.381: T62.3 192.41,24.77 193.04,24.13 193.04,20.32 MQ7.B
N$63
  Top 0.381: T63.3 207.01,25.4 207.65,24.77 207.65,20.32 MQ8.B
N$64
  Top 0.381: T64.3 220.98,24.77 221.62,24.13 221.62,20.32 MQ9.B
N$65
  Top 0.381: T65.3 235.59,25.4 236.22,24.77 236.22,20.32 MQ10.B
N$66
  Top 0.381: T66.3 249.56,24.77 250.19,24.13 250.19,20.32 MQ11.B
N$67
  Top 0.381: T67.3 5.08,24.77 5.71,24.13 5.71,20.32 SC0.B
N$68
  Top 0.381: T68.3 19.68,25.4 20.32,24.77 20.32,20.32 SC1.B
N$69
  Bottom 0.381: T69.3 33.66,24.77 34.29,24.13 34.29,20.32 SC2.B
N$70
  Bottom 0.381: T70.3 48.26,25.4 48.9,24.77 48.9,20.32 SC3.B
N$71
  Bottom 0.381: T71.3 62.23,24.77 62.87,24.13 62.87,20.32 SC4.B
N$72
  Top 0.381: T72.3 78.11,45.72 78.74,45.09 78.74,41.27 LINK.B
N$73
  Bottom 0.381: T73.3 357.5,105.41 363.22,105.41 ION.B
N$74
  Bottom 0.381: T74.3 363.22,93.98 363.22,94.61 364.49,95.89 PAUSE.B
N$75
  Top 0.381: T75.3 357.5,83.19 363.22,83.19 RUN.B
N$76
  Bottom 0.381: T76.3 344.17,107.31 FETCH.B
N$77
  Bottom 0.381: T77.3 337.19,96.52 EXECUTE.B
N$78
  Top 0.381: T78.3 344.17,85.09 DEFER.B
N$79
  Bottom 0.381: T79.3 337.19,74.3 WORDCOUNT.B
N$80
  Bottom 0.381: T80.3 344.17,62.87 CURRENTADDRESS.B
N$81
  Bottom 0.381: T81.3 337.19,52.07 BREAK.B
N$82
  Top 0.381: T82.3 315.6,107.31 AND.B
N$83
  Bottom 0.381: T83.3 308.61,96.52 TAD.B
N$84
  Bottom 0.381: T84.3 315.6,85.09 ISZ.B
N$85
  Bottom 0.381: T85.3 308.61,74.3 DCA.B
N$86
  Bottom 0.381: T86.3 315.6,62.87 JMS.B
N$87
  Bottom 0.381: T87.3 308.61,52.07 JMP.B
N$88
  Bottom 0.381: T88.3 315.6,40.64 IOT.B
N$89
  Bottom 0.381: T89.3 308.61,29.84 OPR.B
OPR
  Top 0.381: T89.2 318.13,28.57 329.56,40.01 329.56,119.38 328.3,120.65 D40.16 328.3,121.28 328.93,121.92 328.93,127 330.2,128.27 F40BOT.11
PAUSE
  Bottom 0.381: 344.81,125.09 344.17,124.46 344.17,118.11 356.87,118.11 367.03,107.95 367.03,104.14 362.58,99.69 362.58,95.25 T74.2 | 344.81,125.09 347.35,125.09 347.35,123.83 D40.31 | 344.81,125.09 342.9,125.09 340.36,127.64 340.36,128.27 339.73,128.91 F40TOP.17
PC0
  Top 0.381: T7.2 102.23,123.19 106.05,123.19 E40.1
  Bottom 0.381: D40TOP.1 114.3,128.91 107.31,128.91 107.31,123.83 E40.1
PC1
  Top 0.381: T8.2 107.95,114.94 116.2,114.94 116.2,120.65 E40.10 117.47,121.28 118.11,121.92 118.11,124.46 120.02,126.36 120.02,128.27 120.65,128.91 D40BOT.5
PC2
  Bottom 0.381: 120.65,124.46 120.02,123.83 E40.11 | 120.65,124.46 121.92,125.73 121.92,128.91 D40TOP.6 | 120.65,124.46 120.65,116.2 T9.2
PC3
  Top 0.381: T10.2 136.53,114.94 135.25,116.2 135.25,120.65 E40.24 133.99,121.28 133.35,121.92 133.35,124.46 134.62,125.73 134.62,128.91 D40BOT.14
PC4
  Bottom 0.381: T11.2 151.13,114.3 153.67,114.3 153.67,100.33 154.94,99.06 154.94,68.58 153.03,66.67 140.97,66.67 140.97,117.47 138.43,120.02 138.43,122.56 137.79,123.19 E40.25 136.53,123.83 135.25,125.09 135.25,128.91 D40TOP.14
PC5
  Top 0.381: 148.59,120.65 147.96,120.65 E40.34 | 148.59,120.65 149.86,120.65 155.57,114.94 165.1,114.94 T12.2 | 148.59,120.65 148.59,128.91 142.88,128.91 D40BOT.19
PC6
  Bottom 0.381: T13.2 179.71,114.94 190.5,114.94 190.5,118.75 194.94,123.19 F40.1 196.22,123.83 196.22,125.09 200.03,128.91 E40TOP.1
PC7
  Top 0.381: 204.47,120.02 205.1,120.65 F40.10 | 204.47,120.02 203.84,119.38 203.84,114.94 193.68,114.94 T14.2 | 204.47,120.02 204.47,124.46 205.74,125.73 205.74,128.27 206.38,128.91 E40BOT.5
PC8
  Bottom 0.381: T15.2 209.55,116.2 209.55,122.56 208.91,123.19 F40.11 207.65,123.83 207.65,128.91 E40TOP.6
PC9
  Top 0.381: 222.25,114.94 222.88,115.57 222.88,120.65 F40.24 | 222.25,114.94 222.25,124.46 220.98,125.73 220.98,128.91 E40BOT.14 | T16.2 222.25,114.94
PC10
  Bottom 0.381: T17.2 236.22,114.94 227.33,114.94 227.33,122.56 226.69,123.19 F40.25 225.43,123.83 220.98,128.27 220.98,128.91 E40TOP.14
PC11
  Top 0.381: 237.49,120.02 236.85,120.65 F40.34 | 237.49,120.02 241.3,116.2 241.3,114.94 250.82,114.94 T18.2 | 237.49,120.02 237.49,128.91 228.6,128.91 E40BOT.19
RUN
  Top 0.381: T75.2 350.52,88.9 350.52,109.86 349.25,111.12 349.25,122.56 349.88,123.19 D40.33
  Bottom 0.381: F40TOP.18 341.63,128.91 341.63,128.27 343.54,126.36 349.88,126.36 349.88,123.83 D40.33
SC0
  Bottom 0.381: 36.83,126.36 34.92,128.27 C40TOP.5 | 36.83,126.36 38.1,125.09 38.1,120.02 33.66,115.57 33.66,55.24 6.35,27.94 T67.2 | 36.83,126.36 36.83,125.73 34.92,123.83 C40.9
SC1
  Top 0.381: 22.86,118.75 23.5,118.75 23.5,120.65 C40.2 | 22.86,118.75 9.53,118.75 5.08,114.3 5.08,42.55 20.32,27.3 T68.2 | 22.86,118.75 22.86,128.91 28.57,128.91 C40BOT.1
SC2
  Top 0.381: T69.2 34.92,27.94 53.34,46.35 53.34,122.56 52.7,123.19 C40.23
  Bottom 0.381: C40TOP.13 47.62,128.91 48.26,128.27 48.26,127 51.44,123.83 C40.23
SC3
  Top 0.381: C40BOT.6 36.83,128.91 36.83,125.73 38.1,124.46 38.1,121.92 37.47,121.28 C40.12
  Bottom 0.381: T70.2 37.47,27.3 37.47,17.14 36.2,15.88 3.81,15.88 3.81,83.82 32.38,112.39 32.38,116.84 36.2,120.65 C40.12
SC4
  Bottom 0.381: 55.88,125.09 55.88,128.91 C40TOP.18 | 55.88,125.09 55.88,119.38 53.34,119.38 48.26,114.3 48.26,43.18 63.5,27.94 T71.2 | 55.88,125.09 62.87,125.09 64.14,123.83 C40.33
TAD
  Top 0.381: F40BOT.2 315.6,128.91 315.6,128.27 312.42,125.09 311.15,125.09 311.15,121.92 311.79,121.28 D40.4
  Bottom 0.381: T83.2 318.13,95.25 319.4,96.52 319.4,119.38 318.77,120.02 318.77,124.46 318.13,125.09 313.69,125.09 313.69,121.92 313.06,121.28 D40.4
WC
  Top 0.381: F40BOT.17 339.73,128.91 340.36,128.27 340.36,127.64 342.9,125.09 344.17,125.09 344.17,121.92 344.81,121.28 D40.30
  Bottom 0.381: T79.2 342.9,73.03 342.9,71.12 344.17,69.85 368.3,69.85 368.3,107.95 356.87,119.38 346.07,119.38 346.07,120.65 D40.30

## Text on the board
Bottom: PDP-8/I Light Board 50045108 | 5404519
